VERSION 5.8 ;
BUSBITCHARS "[]" ;
DIVIDERCHAR "/" ;
UNITS
    DATABASE MICRONS 1000 ;
END UNITS

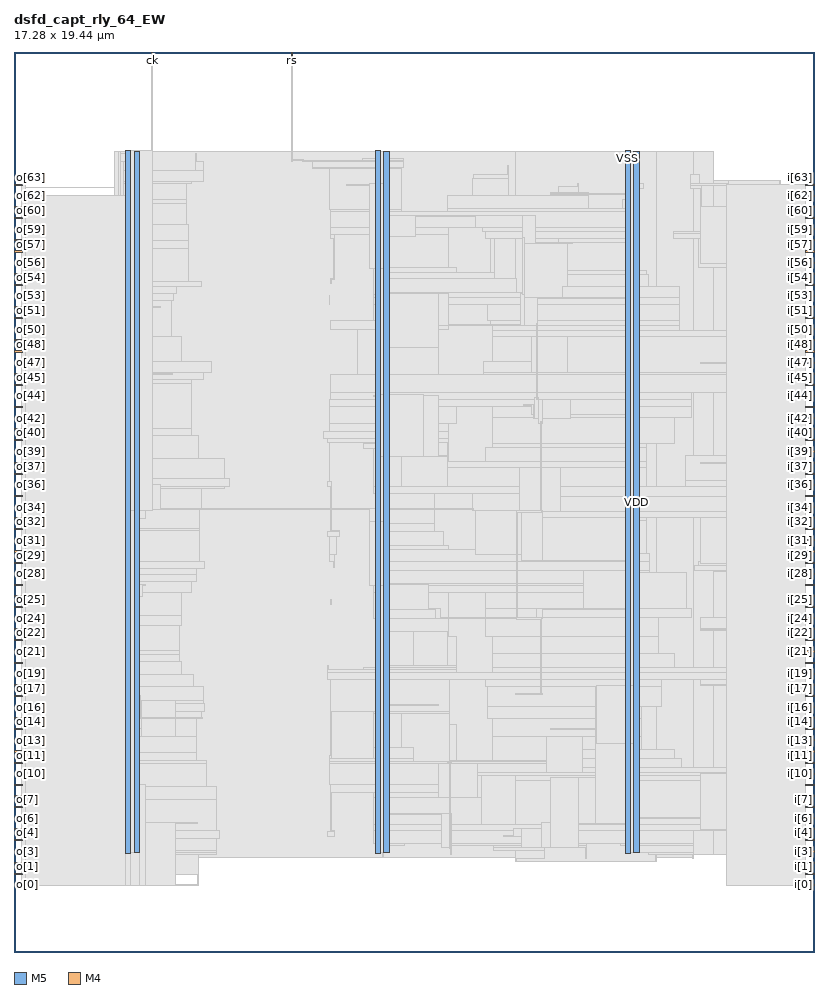
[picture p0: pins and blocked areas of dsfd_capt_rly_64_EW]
MACRO dsfd_capt_rly_64_EW
  FOREIGN dsfd_capt_rly_64_EW 0 0 ;
  CLASS BLOCK ;
  SIZE 17.28 BY 19.44 ;
  PIN ck
    DIRECTION INPUT ;
    USE SIGNAL ;
    PORT
      LAYER M5 ;
        RECT  2.976 19.248 3 19.44 ;
    END
  END ck
  PIN i[0]
    DIRECTION INPUT ;
    USE SIGNAL ;
    PORT
      LAYER M4 ;
        RECT  17.088 1.44 17.28 1.464 ;
    END
  END i[0]
  PIN i[10]
    DIRECTION INPUT ;
    USE SIGNAL ;
    PORT
      LAYER M4 ;
        RECT  17.088 3.84 17.28 3.864 ;
    END
  END i[10]
  PIN i[11]
    DIRECTION INPUT ;
    USE SIGNAL ;
    PORT
      LAYER M4 ;
        RECT  17.088 4.08 17.28 4.104 ;
    END
  END i[11]
  PIN i[12]
    DIRECTION INPUT ;
    USE SIGNAL ;
    PORT
      LAYER M4 ;
        RECT  17.088 4.32 17.28 4.344 ;
    END
  END i[12]
  PIN i[13]
    DIRECTION INPUT ;
    USE SIGNAL ;
    PORT
      LAYER M4 ;
        RECT  17.088 4.56 17.28 4.584 ;
    END
  END i[13]
  PIN i[14]
    DIRECTION INPUT ;
    USE SIGNAL ;
    PORT
      LAYER M4 ;
        RECT  17.088 4.8 17.28 4.824 ;
    END
  END i[14]
  PIN i[15]
    DIRECTION INPUT ;
    USE SIGNAL ;
    PORT
      LAYER M4 ;
        RECT  17.088 5.04 17.28 5.064 ;
    END
  END i[15]
  PIN i[16]
    DIRECTION INPUT ;
    USE SIGNAL ;
    PORT
      LAYER M4 ;
        RECT  17.088 5.28 17.28 5.304 ;
    END
  END i[16]
  PIN i[17]
    DIRECTION INPUT ;
    USE SIGNAL ;
    PORT
      LAYER M4 ;
        RECT  17.088 5.52 17.28 5.544 ;
    END
  END i[17]
  PIN i[18]
    DIRECTION INPUT ;
    USE SIGNAL ;
    PORT
      LAYER M4 ;
        RECT  17.088 5.76 17.28 5.784 ;
    END
  END i[18]
  PIN i[19]
    DIRECTION INPUT ;
    USE SIGNAL ;
    PORT
      LAYER M4 ;
        RECT  17.088 6 17.28 6.024 ;
    END
  END i[19]
  PIN i[1]
    DIRECTION INPUT ;
    USE SIGNAL ;
    PORT
      LAYER M4 ;
        RECT  17.088 1.68 17.28 1.704 ;
    END
  END i[1]
  PIN i[20]
    DIRECTION INPUT ;
    USE SIGNAL ;
    PORT
      LAYER M4 ;
        RECT  17.088 6.24 17.28 6.264 ;
    END
  END i[20]
  PIN i[21]
    DIRECTION INPUT ;
    USE SIGNAL ;
    PORT
      LAYER M4 ;
        RECT  17.088 6.48 17.28 6.504 ;
    END
  END i[21]
  PIN i[22]
    DIRECTION INPUT ;
    USE SIGNAL ;
    PORT
      LAYER M4 ;
        RECT  17.088 6.72 17.28 6.744 ;
    END
  END i[22]
  PIN i[23]
    DIRECTION INPUT ;
    USE SIGNAL ;
    PORT
      LAYER M4 ;
        RECT  17.088 6.96 17.28 6.984 ;
    END
  END i[23]
  PIN i[24]
    DIRECTION INPUT ;
    USE SIGNAL ;
    PORT
      LAYER M4 ;
        RECT  17.088 7.2 17.28 7.224 ;
    END
  END i[24]
  PIN i[25]
    DIRECTION INPUT ;
    USE SIGNAL ;
    PORT
      LAYER M4 ;
        RECT  17.088 7.44 17.28 7.464 ;
    END
  END i[25]
  PIN i[26]
    DIRECTION INPUT ;
    USE SIGNAL ;
    PORT
      LAYER M4 ;
        RECT  17.088 7.68 17.28 7.704 ;
    END
  END i[26]
  PIN i[27]
    DIRECTION INPUT ;
    USE SIGNAL ;
    PORT
      LAYER M4 ;
        RECT  17.088 7.92 17.28 7.944 ;
    END
  END i[27]
  PIN i[28]
    DIRECTION INPUT ;
    USE SIGNAL ;
    PORT
      LAYER M4 ;
        RECT  17.088 8.16 17.28 8.184 ;
    END
  END i[28]
  PIN i[29]
    DIRECTION INPUT ;
    USE SIGNAL ;
    PORT
      LAYER M4 ;
        RECT  17.088 8.4 17.28 8.424 ;
    END
  END i[29]
  PIN i[2]
    DIRECTION INPUT ;
    USE SIGNAL ;
    PORT
      LAYER M4 ;
        RECT  17.088 1.92 17.28 1.944 ;
    END
  END i[2]
  PIN i[30]
    DIRECTION INPUT ;
    USE SIGNAL ;
    PORT
      LAYER M4 ;
        RECT  17.088 8.64 17.28 8.664 ;
    END
  END i[30]
  PIN i[31]
    DIRECTION INPUT ;
    USE SIGNAL ;
    PORT
      LAYER M4 ;
        RECT  17.088 8.88 17.28 8.904 ;
    END
  END i[31]
  PIN i[32]
    DIRECTION INPUT ;
    USE SIGNAL ;
    PORT
      LAYER M4 ;
        RECT  17.088 9.12 17.28 9.144 ;
    END
  END i[32]
  PIN i[33]
    DIRECTION INPUT ;
    USE SIGNAL ;
    PORT
      LAYER M4 ;
        RECT  17.088 9.36 17.28 9.384 ;
    END
  END i[33]
  PIN i[34]
    DIRECTION INPUT ;
    USE SIGNAL ;
    PORT
      LAYER M4 ;
        RECT  17.088 9.6 17.28 9.624 ;
    END
  END i[34]
  PIN i[35]
    DIRECTION INPUT ;
    USE SIGNAL ;
    PORT
      LAYER M4 ;
        RECT  17.088 9.84 17.28 9.864 ;
    END
  END i[35]
  PIN i[36]
    DIRECTION INPUT ;
    USE SIGNAL ;
    PORT
      LAYER M4 ;
        RECT  17.088 10.08 17.28 10.104 ;
    END
  END i[36]
  PIN i[37]
    DIRECTION INPUT ;
    USE SIGNAL ;
    PORT
      LAYER M4 ;
        RECT  17.088 10.32 17.28 10.344 ;
    END
  END i[37]
  PIN i[38]
    DIRECTION INPUT ;
    USE SIGNAL ;
    PORT
      LAYER M4 ;
        RECT  17.088 10.56 17.28 10.584 ;
    END
  END i[38]
  PIN i[39]
    DIRECTION INPUT ;
    USE SIGNAL ;
    PORT
      LAYER M4 ;
        RECT  17.088 10.8 17.28 10.824 ;
    END
  END i[39]
  PIN i[3]
    DIRECTION INPUT ;
    USE SIGNAL ;
    PORT
      LAYER M4 ;
        RECT  17.088 2.16 17.28 2.184 ;
    END
  END i[3]
  PIN i[40]
    DIRECTION INPUT ;
    USE SIGNAL ;
    PORT
      LAYER M4 ;
        RECT  17.088 11.04 17.28 11.064 ;
    END
  END i[40]
  PIN i[41]
    DIRECTION INPUT ;
    USE SIGNAL ;
    PORT
      LAYER M4 ;
        RECT  17.088 11.28 17.28 11.304 ;
    END
  END i[41]
  PIN i[42]
    DIRECTION INPUT ;
    USE SIGNAL ;
    PORT
      LAYER M4 ;
        RECT  17.088 11.52 17.28 11.544 ;
    END
  END i[42]
  PIN i[43]
    DIRECTION INPUT ;
    USE SIGNAL ;
    PORT
      LAYER M4 ;
        RECT  17.088 11.76 17.28 11.784 ;
    END
  END i[43]
  PIN i[44]
    DIRECTION INPUT ;
    USE SIGNAL ;
    PORT
      LAYER M4 ;
        RECT  17.088 12 17.28 12.024 ;
    END
  END i[44]
  PIN i[45]
    DIRECTION INPUT ;
    USE SIGNAL ;
    PORT
      LAYER M4 ;
        RECT  17.088 12.24 17.28 12.264 ;
    END
  END i[45]
  PIN i[46]
    DIRECTION INPUT ;
    USE SIGNAL ;
    PORT
      LAYER M4 ;
        RECT  17.088 12.48 17.28 12.504 ;
    END
  END i[46]
  PIN i[47]
    DIRECTION INPUT ;
    USE SIGNAL ;
    PORT
      LAYER M4 ;
        RECT  17.088 12.72 17.28 12.744 ;
    END
  END i[47]
  PIN i[48]
    DIRECTION INPUT ;
    USE SIGNAL ;
    PORT
      LAYER M4 ;
        RECT  17.088 12.96 17.28 12.984 ;
    END
  END i[48]
  PIN i[49]
    DIRECTION INPUT ;
    USE SIGNAL ;
    PORT
      LAYER M4 ;
        RECT  17.088 13.2 17.28 13.224 ;
    END
  END i[49]
  PIN i[4]
    DIRECTION INPUT ;
    USE SIGNAL ;
    PORT
      LAYER M4 ;
        RECT  17.088 2.4 17.28 2.424 ;
    END
  END i[4]
  PIN i[50]
    DIRECTION INPUT ;
    USE SIGNAL ;
    PORT
      LAYER M4 ;
        RECT  17.088 13.44 17.28 13.464 ;
    END
  END i[50]
  PIN i[51]
    DIRECTION INPUT ;
    USE SIGNAL ;
    PORT
      LAYER M4 ;
        RECT  17.088 13.68 17.28 13.704 ;
    END
  END i[51]
  PIN i[52]
    DIRECTION INPUT ;
    USE SIGNAL ;
    PORT
      LAYER M4 ;
        RECT  17.088 13.92 17.28 13.944 ;
    END
  END i[52]
  PIN i[53]
    DIRECTION INPUT ;
    USE SIGNAL ;
    PORT
      LAYER M4 ;
        RECT  17.088 14.16 17.28 14.184 ;
    END
  END i[53]
  PIN i[54]
    DIRECTION INPUT ;
    USE SIGNAL ;
    PORT
      LAYER M4 ;
        RECT  17.088 14.4 17.28 14.424 ;
    END
  END i[54]
  PIN i[55]
    DIRECTION INPUT ;
    USE SIGNAL ;
    PORT
      LAYER M4 ;
        RECT  17.088 14.64 17.28 14.664 ;
    END
  END i[55]
  PIN i[56]
    DIRECTION INPUT ;
    USE SIGNAL ;
    PORT
      LAYER M4 ;
        RECT  17.088 14.88 17.28 14.904 ;
    END
  END i[56]
  PIN i[57]
    DIRECTION INPUT ;
    USE SIGNAL ;
    PORT
      LAYER M4 ;
        RECT  17.088 15.12 17.28 15.144 ;
    END
  END i[57]
  PIN i[58]
    DIRECTION INPUT ;
    USE SIGNAL ;
    PORT
      LAYER M4 ;
        RECT  17.088 15.36 17.28 15.384 ;
    END
  END i[58]
  PIN i[59]
    DIRECTION INPUT ;
    USE SIGNAL ;
    PORT
      LAYER M4 ;
        RECT  17.088 15.6 17.28 15.624 ;
    END
  END i[59]
  PIN i[5]
    DIRECTION INPUT ;
    USE SIGNAL ;
    PORT
      LAYER M4 ;
        RECT  17.088 2.64 17.28 2.664 ;
    END
  END i[5]
  PIN i[60]
    DIRECTION INPUT ;
    USE SIGNAL ;
    PORT
      LAYER M4 ;
        RECT  17.088 15.84 17.28 15.864 ;
    END
  END i[60]
  PIN i[61]
    DIRECTION INPUT ;
    USE SIGNAL ;
    PORT
      LAYER M4 ;
        RECT  17.088 16.08 17.28 16.104 ;
    END
  END i[61]
  PIN i[62]
    DIRECTION INPUT ;
    USE SIGNAL ;
    PORT
      LAYER M4 ;
        RECT  17.088 16.32 17.28 16.344 ;
    END
  END i[62]
  PIN i[63]
    DIRECTION INPUT ;
    USE SIGNAL ;
    PORT
      LAYER M4 ;
        RECT  17.088 16.56 17.28 16.584 ;
    END
  END i[63]
  PIN i[6]
    DIRECTION INPUT ;
    USE SIGNAL ;
    PORT
      LAYER M4 ;
        RECT  17.088 2.88 17.28 2.904 ;
    END
  END i[6]
  PIN i[7]
    DIRECTION INPUT ;
    USE SIGNAL ;
    PORT
      LAYER M4 ;
        RECT  17.088 3.12 17.28 3.144 ;
    END
  END i[7]
  PIN i[8]
    DIRECTION INPUT ;
    USE SIGNAL ;
    PORT
      LAYER M4 ;
        RECT  17.088 3.36 17.28 3.384 ;
    END
  END i[8]
  PIN i[9]
    DIRECTION INPUT ;
    USE SIGNAL ;
    PORT
      LAYER M4 ;
        RECT  17.088 3.6 17.28 3.624 ;
    END
  END i[9]
  PIN o[0]
    DIRECTION OUTPUT ;
    USE SIGNAL ;
    PORT
      LAYER M4 ;
        RECT  0 1.44 0.192 1.464 ;
    END
  END o[0]
  PIN o[10]
    DIRECTION OUTPUT ;
    USE SIGNAL ;
    PORT
      LAYER M4 ;
        RECT  0 3.84 0.192 3.864 ;
    END
  END o[10]
  PIN o[11]
    DIRECTION OUTPUT ;
    USE SIGNAL ;
    PORT
      LAYER M4 ;
        RECT  0 4.08 0.192 4.104 ;
    END
  END o[11]
  PIN o[12]
    DIRECTION OUTPUT ;
    USE SIGNAL ;
    PORT
      LAYER M4 ;
        RECT  0 4.32 0.192 4.344 ;
    END
  END o[12]
  PIN o[13]
    DIRECTION OUTPUT ;
    USE SIGNAL ;
    PORT
      LAYER M4 ;
        RECT  0 4.56 0.192 4.584 ;
    END
  END o[13]
  PIN o[14]
    DIRECTION OUTPUT ;
    USE SIGNAL ;
    PORT
      LAYER M4 ;
        RECT  0 4.8 0.192 4.824 ;
    END
  END o[14]
  PIN o[15]
    DIRECTION OUTPUT ;
    USE SIGNAL ;
    PORT
      LAYER M4 ;
        RECT  0 5.04 0.192 5.064 ;
    END
  END o[15]
  PIN o[16]
    DIRECTION OUTPUT ;
    USE SIGNAL ;
    PORT
      LAYER M4 ;
        RECT  0 5.28 0.192 5.304 ;
    END
  END o[16]
  PIN o[17]
    DIRECTION OUTPUT ;
    USE SIGNAL ;
    PORT
      LAYER M4 ;
        RECT  0 5.52 0.192 5.544 ;
    END
  END o[17]
  PIN o[18]
    DIRECTION OUTPUT ;
    USE SIGNAL ;
    PORT
      LAYER M4 ;
        RECT  0 5.76 0.192 5.784 ;
    END
  END o[18]
  PIN o[19]
    DIRECTION OUTPUT ;
    USE SIGNAL ;
    PORT
      LAYER M4 ;
        RECT  0 6 0.192 6.024 ;
    END
  END o[19]
  PIN o[1]
    DIRECTION OUTPUT ;
    USE SIGNAL ;
    PORT
      LAYER M4 ;
        RECT  0 1.68 0.192 1.704 ;
    END
  END o[1]
  PIN o[20]
    DIRECTION OUTPUT ;
    USE SIGNAL ;
    PORT
      LAYER M4 ;
        RECT  0 6.24 0.192 6.264 ;
    END
  END o[20]
  PIN o[21]
    DIRECTION OUTPUT ;
    USE SIGNAL ;
    PORT
      LAYER M4 ;
        RECT  0 6.48 0.192 6.504 ;
    END
  END o[21]
  PIN o[22]
    DIRECTION OUTPUT ;
    USE SIGNAL ;
    PORT
      LAYER M4 ;
        RECT  0 6.72 0.192 6.744 ;
    END
  END o[22]
  PIN o[23]
    DIRECTION OUTPUT ;
    USE SIGNAL ;
    PORT
      LAYER M4 ;
        RECT  0 6.96 0.192 6.984 ;
    END
  END o[23]
  PIN o[24]
    DIRECTION OUTPUT ;
    USE SIGNAL ;
    PORT
      LAYER M4 ;
        RECT  0 7.2 0.192 7.224 ;
    END
  END o[24]
  PIN o[25]
    DIRECTION OUTPUT ;
    USE SIGNAL ;
    PORT
      LAYER M4 ;
        RECT  0 7.44 0.192 7.464 ;
    END
  END o[25]
  PIN o[26]
    DIRECTION OUTPUT ;
    USE SIGNAL ;
    PORT
      LAYER M4 ;
        RECT  0 7.68 0.192 7.704 ;
    END
  END o[26]
  PIN o[27]
    DIRECTION OUTPUT ;
    USE SIGNAL ;
    PORT
      LAYER M4 ;
        RECT  0 7.92 0.192 7.944 ;
    END
  END o[27]
  PIN o[28]
    DIRECTION OUTPUT ;
    USE SIGNAL ;
    PORT
      LAYER M4 ;
        RECT  0 8.16 0.192 8.184 ;
    END
  END o[28]
  PIN o[29]
    DIRECTION OUTPUT ;
    USE SIGNAL ;
    PORT
      LAYER M4 ;
        RECT  0 8.4 0.192 8.424 ;
    END
  END o[29]
  PIN o[2]
    DIRECTION OUTPUT ;
    USE SIGNAL ;
    PORT
      LAYER M4 ;
        RECT  0 1.92 0.192 1.944 ;
    END
  END o[2]
  PIN o[30]
    DIRECTION OUTPUT ;
    USE SIGNAL ;
    PORT
      LAYER M4 ;
        RECT  0 8.64 0.192 8.664 ;
    END
  END o[30]
  PIN o[31]
    DIRECTION OUTPUT ;
    USE SIGNAL ;
    PORT
      LAYER M4 ;
        RECT  0 8.88 0.192 8.904 ;
    END
  END o[31]
  PIN o[32]
    DIRECTION OUTPUT ;
    USE SIGNAL ;
    PORT
      LAYER M4 ;
        RECT  0 9.12 0.192 9.144 ;
    END
  END o[32]
  PIN o[33]
    DIRECTION OUTPUT ;
    USE SIGNAL ;
    PORT
      LAYER M4 ;
        RECT  0 9.36 0.192 9.384 ;
    END
  END o[33]
  PIN o[34]
    DIRECTION OUTPUT ;
    USE SIGNAL ;
    PORT
      LAYER M4 ;
        RECT  0 9.6 0.192 9.624 ;
    END
  END o[34]
  PIN o[35]
    DIRECTION OUTPUT ;
    USE SIGNAL ;
    PORT
      LAYER M4 ;
        RECT  0 9.84 0.192 9.864 ;
    END
  END o[35]
  PIN o[36]
    DIRECTION OUTPUT ;
    USE SIGNAL ;
    PORT
      LAYER M4 ;
        RECT  0 10.08 0.192 10.104 ;
    END
  END o[36]
  PIN o[37]
    DIRECTION OUTPUT ;
    USE SIGNAL ;
    PORT
      LAYER M4 ;
        RECT  0 10.32 0.192 10.344 ;
    END
  END o[37]
  PIN o[38]
    DIRECTION OUTPUT ;
    USE SIGNAL ;
    PORT
      LAYER M4 ;
        RECT  0 10.56 0.192 10.584 ;
    END
  END o[38]
  PIN o[39]
    DIRECTION OUTPUT ;
    USE SIGNAL ;
    PORT
      LAYER M4 ;
        RECT  0 10.8 0.192 10.824 ;
    END
  END o[39]
  PIN o[3]
    DIRECTION OUTPUT ;
    USE SIGNAL ;
    PORT
      LAYER M4 ;
        RECT  0 2.16 0.192 2.184 ;
    END
  END o[3]
  PIN o[40]
    DIRECTION OUTPUT ;
    USE SIGNAL ;
    PORT
      LAYER M4 ;
        RECT  0 11.04 0.192 11.064 ;
    END
  END o[40]
  PIN o[41]
    DIRECTION OUTPUT ;
    USE SIGNAL ;
    PORT
      LAYER M4 ;
        RECT  0 11.28 0.192 11.304 ;
    END
  END o[41]
  PIN o[42]
    DIRECTION OUTPUT ;
    USE SIGNAL ;
    PORT
      LAYER M4 ;
        RECT  0 11.52 0.192 11.544 ;
    END
  END o[42]
  PIN o[43]
    DIRECTION OUTPUT ;
    USE SIGNAL ;
    PORT
      LAYER M4 ;
        RECT  0 11.76 0.192 11.784 ;
    END
  END o[43]
  PIN o[44]
    DIRECTION OUTPUT ;
    USE SIGNAL ;
    PORT
      LAYER M4 ;
        RECT  0 12 0.192 12.024 ;
    END
  END o[44]
  PIN o[45]
    DIRECTION OUTPUT ;
    USE SIGNAL ;
    PORT
      LAYER M4 ;
        RECT  0 12.24 0.192 12.264 ;
    END
  END o[45]
  PIN o[46]
    DIRECTION OUTPUT ;
    USE SIGNAL ;
    PORT
      LAYER M4 ;
        RECT  0 12.48 0.192 12.504 ;
    END
  END o[46]
  PIN o[47]
    DIRECTION OUTPUT ;
    USE SIGNAL ;
    PORT
      LAYER M4 ;
        RECT  0 12.72 0.192 12.744 ;
    END
  END o[47]
  PIN o[48]
    DIRECTION OUTPUT ;
    USE SIGNAL ;
    PORT
      LAYER M4 ;
        RECT  0 12.96 0.192 12.984 ;
    END
  END o[48]
  PIN o[49]
    DIRECTION OUTPUT ;
    USE SIGNAL ;
    PORT
      LAYER M4 ;
        RECT  0 13.2 0.192 13.224 ;
    END
  END o[49]
  PIN o[4]
    DIRECTION OUTPUT ;
    USE SIGNAL ;
    PORT
      LAYER M4 ;
        RECT  0 2.4 0.192 2.424 ;
    END
  END o[4]
  PIN o[50]
    DIRECTION OUTPUT ;
    USE SIGNAL ;
    PORT
      LAYER M4 ;
        RECT  0 13.44 0.192 13.464 ;
    END
  END o[50]
  PIN o[51]
    DIRECTION OUTPUT ;
    USE SIGNAL ;
    PORT
      LAYER M4 ;
        RECT  0 13.68 0.192 13.704 ;
    END
  END o[51]
  PIN o[52]
    DIRECTION OUTPUT ;
    USE SIGNAL ;
    PORT
      LAYER M4 ;
        RECT  0 13.92 0.192 13.944 ;
    END
  END o[52]
  PIN o[53]
    DIRECTION OUTPUT ;
    USE SIGNAL ;
    PORT
      LAYER M4 ;
        RECT  0 14.16 0.192 14.184 ;
    END
  END o[53]
  PIN o[54]
    DIRECTION OUTPUT ;
    USE SIGNAL ;
    PORT
      LAYER M4 ;
        RECT  0 14.4 0.192 14.424 ;
    END
  END o[54]
  PIN o[55]
    DIRECTION OUTPUT ;
    USE SIGNAL ;
    PORT
      LAYER M4 ;
        RECT  0 14.64 0.192 14.664 ;
    END
  END o[55]
  PIN o[56]
    DIRECTION OUTPUT ;
    USE SIGNAL ;
    PORT
      LAYER M4 ;
        RECT  0 14.88 0.192 14.904 ;
    END
  END o[56]
  PIN o[57]
    DIRECTION OUTPUT ;
    USE SIGNAL ;
    PORT
      LAYER M4 ;
        RECT  0 15.12 0.192 15.144 ;
    END
  END o[57]
  PIN o[58]
    DIRECTION OUTPUT ;
    USE SIGNAL ;
    PORT
      LAYER M4 ;
        RECT  0 15.36 0.192 15.384 ;
    END
  END o[58]
  PIN o[59]
    DIRECTION OUTPUT ;
    USE SIGNAL ;
    PORT
      LAYER M4 ;
        RECT  0 15.6 0.192 15.624 ;
    END
  END o[59]
  PIN o[5]
    DIRECTION OUTPUT ;
    USE SIGNAL ;
    PORT
      LAYER M4 ;
        RECT  0 2.64 0.192 2.664 ;
    END
  END o[5]
  PIN o[60]
    DIRECTION OUTPUT ;
    USE SIGNAL ;
    PORT
      LAYER M4 ;
        RECT  0 15.84 0.192 15.864 ;
    END
  END o[60]
  PIN o[61]
    DIRECTION OUTPUT ;
    USE SIGNAL ;
    PORT
      LAYER M4 ;
        RECT  0 16.08 0.192 16.104 ;
    END
  END o[61]
  PIN o[62]
    DIRECTION OUTPUT ;
    USE SIGNAL ;
    PORT
      LAYER M4 ;
        RECT  0 16.32 0.192 16.344 ;
    END
  END o[62]
  PIN o[63]
    DIRECTION OUTPUT ;
    USE SIGNAL ;
    PORT
      LAYER M4 ;
        RECT  0 16.56 0.192 16.584 ;
    END
  END o[63]
  PIN o[6]
    DIRECTION OUTPUT ;
    USE SIGNAL ;
    PORT
      LAYER M4 ;
        RECT  0 2.88 0.192 2.904 ;
    END
  END o[6]
  PIN o[7]
    DIRECTION OUTPUT ;
    USE SIGNAL ;
    PORT
      LAYER M4 ;
        RECT  0 3.12 0.192 3.144 ;
    END
  END o[7]
  PIN o[8]
    DIRECTION OUTPUT ;
    USE SIGNAL ;
    PORT
      LAYER M4 ;
        RECT  0 3.36 0.192 3.384 ;
    END
  END o[8]
  PIN o[9]
    DIRECTION OUTPUT ;
    USE SIGNAL ;
    PORT
      LAYER M4 ;
        RECT  0 3.6 0.192 3.624 ;
    END
  END o[9]
  PIN rs
    DIRECTION INPUT ;
    USE SIGNAL ;
    PORT
      LAYER M5 ;
        RECT  6 19.248 6.024 19.44 ;
    END
  END rs
  PIN VDD
    DIRECTION INOUT ;
    USE POWER ;
    PORT
      LAYER M5 ;
        RECT  13.392 2.151 13.512 17.289 ;
        RECT  7.992 2.151 8.112 17.289 ;
        RECT  2.592 2.151 2.712 17.289 ;
    END
  END VDD
  PIN VSS
    DIRECTION INOUT ;
    USE GROUND ;
    PORT
      LAYER M5 ;
        RECT  13.2 2.137 13.32 17.303 ;
        RECT  7.8 2.137 7.92 17.303 ;
        RECT  2.4 2.137 2.52 17.303 ;
    END
  END VSS
  OBS
    LAYER RVTN ;
     RECT  2.16 2.16 15.12 2.295 ;
     RECT  2.16 2.565 15.12 2.835 ;
     RECT  2.16 3.105 15.12 3.375 ;
     RECT  2.16 3.645 15.12 3.915 ;
     RECT  2.16 4.185 15.12 4.455 ;
     RECT  2.16 4.725 15.12 4.995 ;
     RECT  2.16 5.265 15.12 5.535 ;
     RECT  2.16 5.805 15.12 6.075 ;
     RECT  2.16 6.345 15.12 6.615 ;
     RECT  2.16 6.885 15.12 7.155 ;
     RECT  2.16 7.425 15.12 7.695 ;
     RECT  2.16 7.965 15.12 8.235 ;
     RECT  2.16 8.505 15.12 8.775 ;
     RECT  2.16 9.045 15.12 9.315 ;
     RECT  2.16 9.585 15.12 9.855 ;
     RECT  2.16 10.125 15.12 10.395 ;
     RECT  2.16 10.665 15.12 10.935 ;
     RECT  2.16 11.205 15.12 11.475 ;
     RECT  2.16 11.745 15.12 12.015 ;
     RECT  2.16 12.285 15.12 12.555 ;
     RECT  2.16 12.825 15.12 13.095 ;
     RECT  2.16 13.365 15.12 13.635 ;
     RECT  2.16 13.905 15.12 14.175 ;
     RECT  2.16 14.445 15.12 14.715 ;
     RECT  2.16 14.985 15.12 15.255 ;
     RECT  2.16 15.525 15.12 15.795 ;
     RECT  2.16 16.065 15.12 16.335 ;
     RECT  2.16 16.605 15.12 16.875 ;
     RECT  2.16 17.145 15.12 17.28 ;
    LAYER RVTP ;
     RECT  2.16 2.295 15.12 2.565 ;
     RECT  2.16 2.835 15.12 3.105 ;
     RECT  2.16 3.375 15.12 3.645 ;
     RECT  2.16 3.915 15.12 4.185 ;
     RECT  2.16 4.455 15.12 4.725 ;
     RECT  2.16 4.995 15.12 5.265 ;
     RECT  2.16 5.535 15.12 5.805 ;
     RECT  2.16 6.075 15.12 6.345 ;
     RECT  2.16 6.615 15.12 6.885 ;
     RECT  2.16 7.155 15.12 7.425 ;
     RECT  2.16 7.695 15.12 7.965 ;
     RECT  2.16 8.235 15.12 8.505 ;
     RECT  2.16 8.775 15.12 9.045 ;
     RECT  2.16 9.315 15.12 9.585 ;
     RECT  2.16 9.855 15.12 10.125 ;
     RECT  2.16 10.395 15.12 10.665 ;
     RECT  2.16 10.935 15.12 11.205 ;
     RECT  2.16 11.475 15.12 11.745 ;
     RECT  2.16 12.015 15.12 12.285 ;
     RECT  2.16 12.555 15.12 12.825 ;
     RECT  2.16 13.095 15.12 13.365 ;
     RECT  2.16 13.635 15.12 13.905 ;
     RECT  2.16 14.175 15.12 14.445 ;
     RECT  2.16 14.715 15.12 14.985 ;
     RECT  2.16 15.255 15.12 15.525 ;
     RECT  2.16 15.795 15.12 16.065 ;
     RECT  2.16 16.335 15.12 16.605 ;
     RECT  2.16 16.875 15.12 17.145 ;
    LAYER M1 ;
     RECT  2.16 2.151 15.12 17.289 ;
    LAYER M2 ;
     RECT  0.211 16.506 2.16 16.524 ;
     RECT  2.16 2.151 2.263 17.289 ;
     RECT  2.263 2.106 2.299 17.289 ;
     RECT  2.299 2.034 10.831 17.289 ;
     RECT  10.831 1.962 13.883 17.289 ;
     RECT  13.883 2.034 14.675 17.289 ;
     RECT  14.675 2.106 15.12 17.289 ;
     RECT  15.12 2.106 15.431 8.226 ;
     RECT  15.12 9.018 15.431 16.668 ;
     RECT  15.431 2.106 15.467 3.708 ;
     RECT  15.431 4.968 15.467 5.598 ;
     RECT  15.431 7.668 15.467 8.028 ;
     RECT  15.431 10.17 15.467 10.89 ;
     RECT  15.431 11.79 15.467 12.384 ;
     RECT  15.431 13.95 15.467 14.508 ;
     RECT  15.467 14.22 15.503 14.508 ;
     RECT  15.467 11.79 16.007 11.97 ;
     RECT  15.467 2.106 16.547 2.394 ;
     RECT  15.467 5.31 16.547 5.328 ;
     RECT  15.467 8.01 16.547 8.028 ;
     RECT  15.467 10.872 16.547 10.89 ;
     RECT  16.007 11.79 16.547 11.808 ;
     RECT  15.503 14.49 16.547 14.508 ;
     RECT  15.431 16.074 16.547 16.668 ;
     RECT  16.547 2.106 16.583 2.124 ;
    LAYER M3 ;
     RECT  3.96 1.435 3.978 1.675 ;
     RECT  16.524 1.675 16.542 1.915 ;
     RECT  10.836 1.957 10.854 2.029 ;
     RECT  2.304 2.029 2.322 2.101 ;
     RECT  3.42 1.675 3.978 2.101 ;
     RECT  13.86 1.957 13.878 2.101 ;
     RECT  14.652 2.029 14.67 2.101 ;
     RECT  16.524 1.915 16.578 2.129 ;
     RECT  2.268 2.101 2.322 2.143 ;
     RECT  3.06 2.101 4.374 2.143 ;
     RECT  7.956 2.065 7.974 2.143 ;
     RECT  13.716 2.101 14.67 2.143 ;
     RECT  15.408 1.435 15.426 2.155 ;
     RECT  2.268 2.143 4.374 2.189 ;
     RECT  10.836 2.029 11.466 2.191 ;
     RECT  9.432 2.101 9.45 2.251 ;
     RECT  10.368 2.191 11.466 2.251 ;
     RECT  12.348 2.029 12.366 2.251 ;
     RECT  7.815 2.143 7.974 2.299 ;
     RECT  9.252 2.251 9.45 2.299 ;
     RECT  10.368 2.251 12.366 2.299 ;
     RECT  13.215 2.143 14.67 2.299 ;
     RECT  7.815 2.299 8.442 2.335 ;
     RECT  9.252 2.299 12.366 2.335 ;
     RECT  13.104 2.299 14.67 2.335 ;
     RECT  16.524 2.129 16.542 2.399 ;
     RECT  2.304 2.189 4.374 2.461 ;
     RECT  6.768 2.497 6.93 2.597 ;
     RECT  2.304 2.461 4.446 2.633 ;
     RECT  6.84 2.597 6.93 2.633 ;
     RECT  7.776 2.335 14.67 2.635 ;
     RECT  15.408 2.155 15.462 2.635 ;
     RECT  7.776 2.635 15.462 2.759 ;
     RECT  0.216 2.299 0.234 2.813 ;
     RECT  2.304 2.633 4.374 3.299 ;
     RECT  7.776 2.759 10.098 3.335 ;
     RECT  6.84 2.633 6.858 3.451 ;
     RECT  7.776 3.335 9.162 3.451 ;
     RECT  2.34 3.299 4.374 3.569 ;
     RECT  6.84 3.451 9.162 3.613 ;
     RECT  10.836 2.759 15.462 3.713 ;
     RECT  10.008 3.335 10.098 3.811 ;
     RECT  10.836 3.713 15.426 3.811 ;
     RECT  10.008 3.811 15.426 3.875 ;
     RECT  12.276 3.875 15.426 3.983 ;
     RECT  2.34 3.569 4.158 4.075 ;
     RECT  6.804 3.613 9.162 4.075 ;
     RECT  10.008 3.875 11.502 4.075 ;
     RECT  6.804 4.075 11.502 4.109 ;
     RECT  2.304 4.075 4.158 4.145 ;
     RECT  9.396 4.109 11.502 4.145 ;
     RECT  6.804 4.109 8.622 4.181 ;
     RECT  12.276 3.983 14.418 4.181 ;
     RECT  6.804 4.181 6.858 4.253 ;
     RECT  2.304 4.145 3.942 4.315 ;
     RECT  12.276 4.181 14.274 4.379 ;
     RECT  7.776 4.181 8.622 4.415 ;
     RECT  2.268 4.315 3.942 4.649 ;
     RECT  10.332 4.145 11.502 4.657 ;
     RECT  12.276 4.379 13.554 4.657 ;
     RECT  15.408 3.983 15.426 4.792 ;
     RECT  2.268 4.649 2.754 4.829 ;
     RECT  9.396 4.145 9.558 4.919 ;
     RECT  3.492 4.649 3.942 5.035 ;
     RECT  10.332 4.657 13.554 5.035 ;
     RECT  7.776 4.415 8.37 5.161 ;
     RECT  9.396 4.919 9.414 5.161 ;
     RECT  3.492 5.035 4.05 5.197 ;
     RECT  6.84 4.253 6.858 5.197 ;
     RECT  7.776 5.161 9.414 5.197 ;
     RECT  10.224 5.035 13.554 5.305 ;
     RECT  16.524 5.035 16.542 5.333 ;
     RECT  3.492 5.197 4.122 5.369 ;
     RECT  2.304 4.829 2.754 5.431 ;
     RECT  3.492 5.369 4.086 5.431 ;
     RECT  15.408 4.792 15.462 5.603 ;
     RECT  2.304 5.431 4.086 5.729 ;
     RECT  10.224 5.305 13.986 5.737 ;
     RECT  15.408 5.603 15.426 5.755 ;
     RECT  6.84 5.197 9.414 5.881 ;
     RECT  10.188 5.737 13.986 5.881 ;
     RECT  14.832 5.755 15.426 5.881 ;
     RECT  2.304 5.729 3.87 5.999 ;
     RECT  6.768 5.881 15.426 6.035 ;
     RECT  6.768 6.035 9.558 6.107 ;
     RECT  7.56 6.107 9.558 6.143 ;
     RECT  10.332 6.035 15.426 6.143 ;
     RECT  6.768 6.107 6.786 6.179 ;
     RECT  7.815 6.143 9.558 6.179 ;
     RECT  2.304 5.999 3.618 6.269 ;
     RECT  2.304 6.269 3.582 6.421 ;
     RECT  10.332 6.143 14.274 6.449 ;
     RECT  2.268 6.421 3.582 6.509 ;
     RECT  9.36 6.179 9.558 6.809 ;
     RECT  10.332 6.449 13.914 6.817 ;
     RECT  7.815 6.179 8.622 6.925 ;
     RECT  9.36 6.809 9.378 6.925 ;
     RECT  15.408 6.143 15.426 6.955 ;
     RECT  2.304 6.509 3.582 7.051 ;
     RECT  7.815 6.925 9.378 7.195 ;
     RECT  14.832 6.955 15.426 7.223 ;
     RECT  10.188 6.817 13.914 7.231 ;
     RECT  2.304 7.051 3.618 7.259 ;
     RECT  15.408 7.223 15.426 7.42 ;
     RECT  10.188 7.231 14.634 7.421 ;
     RECT  10.188 7.421 14.526 7.427 ;
     RECT  6.84 7.501 6.858 7.619 ;
     RECT  15.408 7.42 15.462 7.691 ;
     RECT  2.376 7.259 3.618 7.771 ;
     RECT  7.776 7.195 9.378 7.771 ;
     RECT  10.188 7.427 12.294 7.771 ;
     RECT  7.776 7.771 12.294 7.925 ;
     RECT  7.812 7.925 12.294 7.949 ;
     RECT  2.376 7.771 3.834 8.005 ;
     RECT  16.524 7.915 16.542 8.033 ;
     RECT  2.34 8.005 3.942 8.155 ;
     RECT  13.215 7.427 14.526 8.195 ;
     RECT  7.815 7.949 12.294 8.239 ;
     RECT  13.215 8.195 13.734 8.239 ;
     RECT  15.408 7.691 15.426 8.239 ;
     RECT  2.304 8.155 3.942 8.275 ;
     RECT  14.688 8.239 15.426 8.339 ;
     RECT  2.304 8.275 4.122 8.429 ;
     RECT  7.815 8.239 13.734 8.429 ;
     RECT  14.796 8.339 15.426 8.429 ;
     RECT  6.912 8.311 6.93 8.437 ;
     RECT  6.804 8.437 6.93 8.581 ;
     RECT  11.808 8.429 13.734 8.609 ;
     RECT  7.815 8.429 10.998 8.699 ;
     RECT  7.815 8.699 9.378 8.771 ;
     RECT  6.804 8.581 6.966 8.977 ;
     RECT  6.768 8.977 7.038 9.077 ;
     RECT  7.815 8.771 9.27 9.077 ;
     RECT  2.304 8.429 4.014 9.112 ;
     RECT  6.84 9.077 7.038 9.113 ;
     RECT  2.268 9.112 4.014 9.149 ;
     RECT  7.815 9.077 9.09 9.259 ;
     RECT  10.116 8.699 10.998 9.319 ;
     RECT  11.808 8.609 13.662 9.319 ;
     RECT  10.116 9.319 13.662 9.391 ;
     RECT  14.832 8.429 15.426 9.391 ;
     RECT  10.116 9.391 15.426 9.509 ;
     RECT  10.116 9.509 10.998 9.544 ;
     RECT  9.9 9.544 10.998 9.545 ;
     RECT  2.304 9.149 4.014 9.589 ;
     RECT  11.808 9.509 15.426 9.835 ;
     RECT  7.812 9.259 9.09 9.895 ;
     RECT  9.9 9.545 10.926 9.895 ;
     RECT  2.304 9.589 4.05 10.021 ;
     RECT  7.776 9.895 10.926 10.049 ;
     RECT  11.808 9.835 15.462 10.049 ;
     RECT  2.304 10.021 4.554 10.057 ;
     RECT  6.84 9.113 6.858 10.057 ;
     RECT  6.768 10.057 6.858 10.157 ;
     RECT  14.508 10.049 15.462 10.193 ;
     RECT  2.304 10.057 4.662 10.229 ;
     RECT  9.36 10.049 10.926 10.471 ;
     RECT  11.808 10.049 13.662 10.471 ;
     RECT  9.36 10.471 13.662 10.589 ;
     RECT  2.304 10.229 4.554 10.661 ;
     RECT  14.508 10.193 15.426 10.733 ;
     RECT  0.216 10.699 0.234 10.829 ;
     RECT  7.776 10.049 8.37 10.867 ;
     RECT  10.188 10.589 13.662 10.895 ;
     RECT  7.56 10.867 8.37 10.975 ;
     RECT  10.332 10.895 13.662 10.975 ;
     RECT  6.804 10.157 6.822 11.011 ;
     RECT  7.56 10.975 8.622 11.011 ;
     RECT  9.36 10.589 9.378 11.011 ;
     RECT  6.768 11.011 9.378 11.101 ;
     RECT  2.304 10.661 3.978 11.165 ;
     RECT  6.696 11.101 9.378 11.237 ;
     RECT  2.304 11.165 3.834 11.315 ;
     RECT  6.804 11.237 9.378 11.407 ;
     RECT  10.332 10.975 14.274 11.551 ;
     RECT  6.804 11.407 9.558 11.785 ;
     RECT  10.332 11.551 14.634 11.785 ;
     RECT  16.524 10.795 16.542 11.813 ;
     RECT  6.804 11.785 14.634 11.939 ;
     RECT  15.408 10.733 15.426 11.947 ;
     RECT  15.408 11.947 16.002 12.029 ;
     RECT  6.84 11.939 14.634 12.091 ;
     RECT  15.408 12.029 15.462 12.091 ;
     RECT  2.376 11.315 3.834 12.289 ;
     RECT  2.304 12.289 3.834 12.361 ;
     RECT  6.84 12.091 15.462 12.479 ;
     RECT  10.152 12.479 15.462 12.509 ;
     RECT  10.152 12.509 15.426 12.515 ;
     RECT  2.304 12.361 4.086 12.523 ;
     RECT  2.304 12.523 4.266 12.749 ;
     RECT  10.152 12.515 11.178 12.749 ;
     RECT  2.304 12.749 3.618 13.289 ;
     RECT  10.332 12.749 11.178 13.297 ;
     RECT  11.952 12.515 15.426 13.297 ;
     RECT  10.332 13.297 15.426 13.433 ;
     RECT  7.416 12.479 9.162 13.441 ;
     RECT  10.332 13.433 14.382 13.531 ;
     RECT  6.84 13.441 9.378 13.631 ;
     RECT  10.296 13.531 14.382 13.639 ;
     RECT  15.408 13.433 15.426 13.675 ;
     RECT  15.408 13.675 15.462 13.915 ;
     RECT  7.776 13.631 9.378 13.981 ;
     RECT  10.224 13.639 14.382 13.981 ;
     RECT  2.304 13.289 3.402 14.071 ;
     RECT  7.776 13.981 14.382 14.141 ;
     RECT  6.804 13.981 6.822 14.171 ;
     RECT  2.304 14.071 3.438 14.215 ;
     RECT  7.776 14.141 10.998 14.243 ;
     RECT  15.408 13.915 15.498 14.243 ;
     RECT  11.844 14.141 14.382 14.369 ;
     RECT  2.304 14.215 3.51 14.377 ;
     RECT  2.304 14.377 4.05 14.477 ;
     RECT  16.524 14.395 16.542 14.513 ;
     RECT  6.84 14.449 6.858 14.521 ;
     RECT  6.84 14.521 6.93 14.549 ;
     RECT  7.776 14.243 10.854 14.549 ;
     RECT  11.952 14.369 13.698 14.639 ;
     RECT  7.776 14.549 10.386 14.675 ;
     RECT  11.952 14.639 13.662 14.711 ;
     RECT  7.776 14.675 9.558 14.783 ;
     RECT  15.408 14.243 15.426 14.791 ;
     RECT  2.304 14.477 3.762 15.187 ;
     RECT  11.952 14.711 13.497 15.331 ;
     RECT  2.268 15.187 3.762 15.359 ;
     RECT  0.216 15.259 0.234 15.389 ;
     RECT  10.296 14.675 10.386 15.403 ;
     RECT  6.912 14.549 6.93 15.421 ;
     RECT  10.296 15.403 11.034 15.421 ;
     RECT  11.772 15.331 13.497 15.421 ;
     RECT  14.796 14.791 15.426 15.421 ;
     RECT  6.84 15.421 6.93 15.493 ;
     RECT  7.776 14.783 9.378 15.493 ;
     RECT  14.256 15.421 15.426 15.521 ;
     RECT  14.256 15.521 14.85 15.557 ;
     RECT  10.188 15.421 13.497 15.565 ;
     RECT  6.84 15.493 9.378 15.643 ;
     RECT  10.116 15.565 13.497 15.643 ;
     RECT  2.304 15.359 3.762 15.719 ;
     RECT  6.84 15.643 13.497 15.989 ;
     RECT  6.84 15.989 8.37 16.033 ;
     RECT  9.36 15.989 13.497 16.061 ;
     RECT  2.304 15.719 3.726 16.169 ;
     RECT  2.34 16.169 3.726 16.259 ;
     RECT  13.14 16.061 13.497 16.259 ;
     RECT  9.36 16.061 12.402 16.331 ;
     RECT  11.592 16.331 12.402 16.397 ;
     RECT  11.772 16.397 12.402 16.403 ;
     RECT  13.215 16.259 13.497 16.501 ;
     RECT  14.832 15.557 14.85 16.501 ;
     RECT  11.772 16.403 12.186 16.529 ;
     RECT  14.616 16.501 14.85 16.555 ;
     RECT  0.216 16.501 0.234 16.589 ;
     RECT  12.168 16.529 12.186 16.601 ;
     RECT  13.215 16.501 13.59 16.601 ;
     RECT  14.616 16.555 15.426 16.601 ;
     RECT  2.376 16.259 3.726 16.609 ;
     RECT  2.376 16.609 3.834 16.645 ;
     RECT  16.524 15.835 16.542 16.673 ;
     RECT  9.9 16.331 10.674 16.709 ;
     RECT  9.936 16.709 10.674 16.799 ;
     RECT  14.616 16.601 14.814 16.799 ;
     RECT  2.376 16.645 4.086 16.871 ;
     RECT  6.804 16.033 8.37 16.915 ;
     RECT  6.444 16.915 8.37 16.951 ;
     RECT  10.656 16.799 10.674 16.979 ;
     RECT  13.215 16.601 13.497 17.027 ;
     RECT  2.376 16.871 2.79 17.069 ;
     RECT  3.924 16.871 4.086 17.069 ;
     RECT  2.376 17.069 2.505 17.077 ;
     RECT  6.444 16.951 8.406 17.077 ;
     RECT  6.228 17.077 8.406 17.105 ;
     RECT  6.228 17.105 6.246 17.117 ;
     RECT  7.524 17.105 8.406 17.141 ;
     RECT  2.304 17.077 2.505 17.249 ;
     RECT  3.924 17.069 3.942 17.249 ;
     RECT  2.415 17.249 2.505 17.297 ;
     RECT  7.815 17.141 7.905 17.297 ;
     RECT  13.215 17.027 13.305 17.297 ;
    LAYER M4 ;
     RECT  0.156 1.44 0.245 16.584 ;
     RECT  0.245 1.44 2.408 16.344 ;
     RECT  2.408 1.44 2.512 17.292 ;
     RECT  2.512 1.44 2.704 17.022 ;
     RECT  2.704 5.04 2.729 5.544 ;
     RECT  2.704 7.68 2.765 7.944 ;
     RECT  2.704 16.32 2.765 16.344 ;
     RECT  2.704 1.44 2.837 3.624 ;
     RECT  2.765 7.92 2.837 7.944 ;
     RECT  2.704 9.36 2.837 10.728 ;
     RECT  2.704 12.24 2.837 12.504 ;
     RECT  2.837 9.552 2.873 10.728 ;
     RECT  2.704 13.92 2.873 15.288 ;
     RECT  2.873 9.552 3.161 10.104 ;
     RECT  2.873 13.92 3.161 13.944 ;
     RECT  2.837 12.48 3.413 12.504 ;
     RECT  2.837 1.44 3.485 2.808 ;
     RECT  3.485 2.784 3.953 2.808 ;
     RECT  3.485 1.44 3.989 1.464 ;
     RECT  2.729 5.04 4.061 5.064 ;
     RECT  5.989 17.088 6.257 17.112 ;
     RECT  3.161 9.552 7.669 9.576 ;
     RECT  7.189 16.56 7.669 16.584 ;
     RECT  7.669 14.784 7.765 14.808 ;
     RECT  7.669 7.92 7.808 7.944 ;
     RECT  7.669 9.264 7.808 9.576 ;
     RECT  7.765 12 7.808 12.024 ;
     RECT  7.765 14.208 7.808 14.808 ;
     RECT  7.669 15.84 7.808 16.584 ;
     RECT  7.808 2.148 7.912 17.292 ;
     RECT  7.912 2.418 8.104 17.022 ;
     RECT  8.104 15.456 8.669 15.912 ;
     RECT  8.104 7.392 8.957 7.944 ;
     RECT  8.957 7.392 9.097 7.416 ;
     RECT  8.104 5.328 9.173 5.352 ;
     RECT  8.104 10.704 9.173 12.024 ;
     RECT  8.104 13.056 9.173 14.232 ;
     RECT  9.097 7.2 9.209 7.416 ;
     RECT  8.104 2.976 9.241 3 ;
     RECT  9.173 10.704 9.389 10.728 ;
     RECT  9.173 13.536 9.389 14.232 ;
     RECT  9.241 2.256 9.443 3 ;
     RECT  9.356 4.08 9.443 4.104 ;
     RECT  8.104 9.552 9.929 9.576 ;
     RECT  8.669 15.888 9.961 15.912 ;
     RECT  10.573 2.496 10.789 2.52 ;
     RECT  9.389 13.536 10.94 13.56 ;
     RECT  10.789 2.496 10.969 2.664 ;
     RECT  9.961 8.592 10.969 9.528 ;
     RECT  9.961 15.648 10.981 15.912 ;
     RECT  10.94 13.536 11.027 14.232 ;
     RECT  11.005 11.808 11.185 11.832 ;
     RECT  11.185 11.616 11.221 11.832 ;
     RECT  11.221 11.52 11.249 11.832 ;
     RECT  10.981 15.312 11.261 15.912 ;
     RECT  9.209 7.2 11.293 7.224 ;
     RECT  11.027 13.536 11.315 14.136 ;
     RECT  11.249 11.52 11.324 11.976 ;
     RECT  11.324 11.424 11.333 11.976 ;
     RECT  10.969 2.256 11.401 2.664 ;
     RECT  10.825 5.568 11.411 5.592 ;
     RECT  11.293 7.2 11.411 7.416 ;
     RECT  10.969 8.448 11.411 9.528 ;
     RECT  11.333 11.424 11.411 11.928 ;
     RECT  11.401 2.256 11.581 2.808 ;
     RECT  11.411 11.52 12.017 11.928 ;
     RECT  11.261 15.312 12.053 15.336 ;
     RECT  11.581 2.256 12.197 3.768 ;
     RECT  12.197 2.784 12.553 3.768 ;
     RECT  11.581 4.8 12.553 4.824 ;
     RECT  12.553 2.784 12.565 4.824 ;
     RECT  12.565 2.784 13.208 5.736 ;
     RECT  11.411 7.392 13.208 7.416 ;
     RECT  11.411 8.448 13.208 9.384 ;
     RECT  12.017 11.616 13.208 11.928 ;
     RECT  11.315 14.112 13.208 14.136 ;
     RECT  11.581 16.368 13.208 16.392 ;
     RECT  13.208 2.148 13.312 17.292 ;
     RECT  13.312 2.418 13.504 17.022 ;
     RECT  13.504 2.88 14.821 2.904 ;
     RECT  14.821 2.64 15.397 3.864 ;
     RECT  14.821 5.76 15.397 5.784 ;
     RECT  14.821 6.96 15.397 6.984 ;
     RECT  14.821 8.4 15.397 9.384 ;
     RECT  14.821 10.56 15.397 10.584 ;
     RECT  14.821 12.72 15.397 12.744 ;
     RECT  14.821 14.88 15.397 16.104 ;
     RECT  15.397 1.44 17.1 16.584 ;
    LAYER M5 ;
     RECT  2.4 2.137 2.52 2.151 ;
     RECT  7.8 2.137 7.92 2.151 ;
     RECT  13.2 2.137 13.32 2.151 ;
     RECT  9.408 2.245 9.432 4.115 ;
     RECT  13.2 2.151 13.512 4.501 ;
     RECT  12.576 4.501 13.512 5.747 ;
     RECT  11.376 5.557 11.4 7.189 ;
     RECT  10.848 7.189 11.4 7.235 ;
     RECT  7.8 2.151 8.112 7.909 ;
     RECT  7.68 7.909 8.112 9.299 ;
     RECT  10.848 7.235 10.872 9.493 ;
     RECT  10.848 9.493 11.4 9.539 ;
     RECT  2.4 2.151 2.712 9.541 ;
     RECT  7.8 9.299 8.112 10.693 ;
     RECT  11.376 9.539 11.4 11.459 ;
     RECT  7.8 10.693 8.856 12.035 ;
     RECT  11.28 11.941 11.304 13.571 ;
     RECT  7.8 12.035 8.112 14.773 ;
     RECT  10.992 14.197 11.016 15.443 ;
     RECT  7.68 14.773 8.112 16.595 ;
     RECT  7.8 16.595 8.112 17.289 ;
     RECT  13.2 5.747 13.512 17.289 ;
     RECT  2.4 9.541 3 17.303 ;
     RECT  7.8 17.289 7.92 17.303 ;
     RECT  13.2 17.289 13.32 17.303 ;
     RECT  2.976 17.303 3 19.28 ;
     RECT  6 17.077 6.024 19.28 ;
  END
END dsfd_capt_rly_64_EW
END LIBRARY
